VERSION 5.7 ;
BUSBITCHARS "[]" ;
DIVIDERCHAR "/" ;

SITE DoubleExtSite
  SYMMETRY X Y ;
  CLASS CORE ;
  SIZE 0.19 BY 2.8 ;
END DoubleExtSite

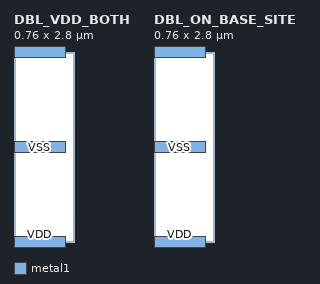
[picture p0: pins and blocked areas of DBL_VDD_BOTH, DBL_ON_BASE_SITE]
MACRO DBL_VDD_BOTH
  CLASS CORE ;
  ORIGIN 0 0 ;
  SIZE 0.76 BY 2.8 ;
  SYMMETRY X Y ;
  SITE DoubleExtSite ;
  PIN VDD
    DIRECTION INOUT ;
    USE POWER ;
    SHAPE ABUTMENT ;
    PORT
      LAYER metal1 ;
        RECT 0 -0.085 0.76 0.085 ;
        RECT 0 2.715 0.76 2.885 ;
    END
  END VDD
  PIN VSS
    DIRECTION INOUT ;
    USE GROUND ;
    SHAPE ABUTMENT ;
    PORT
      LAYER metal1 ;
        RECT 0 1.315 0.76 1.485 ;
    END
  END VSS
END DBL_VDD_BOTH

# Double-height cell tagged with the single-height site; must not vote for
# that site's rail phase.
MACRO DBL_ON_BASE_SITE
  CLASS CORE ;
  ORIGIN 0 0 ;
  SIZE 0.76 BY 2.8 ;
  SYMMETRY X Y ;
  SITE FreePDK45_38x28_10R_NP_162NW_34O ;
  PIN VDD
    DIRECTION INOUT ;
    USE POWER ;
    SHAPE ABUTMENT ;
    PORT
      LAYER metal1 ;
        RECT 0 -0.085 0.76 0.085 ;
        RECT 0 2.715 0.76 2.885 ;
    END
  END VDD
  PIN VSS
    DIRECTION INOUT ;
    USE GROUND ;
    SHAPE ABUTMENT ;
    PORT
      LAYER metal1 ;
        RECT 0 1.315 0.76 1.485 ;
    END
  END VSS
END DBL_ON_BASE_SITE

END LIBRARY
